# Generated by FakeRAM 2.0
VERSION 5.7 ;
BUSBITCHARS "[]" ;
PROPERTYDEFINITIONS
  MACRO width INTEGER ;
  MACRO depth INTEGER ;
  MACRO banks INTEGER ;
END PROPERTYDEFINITIONS
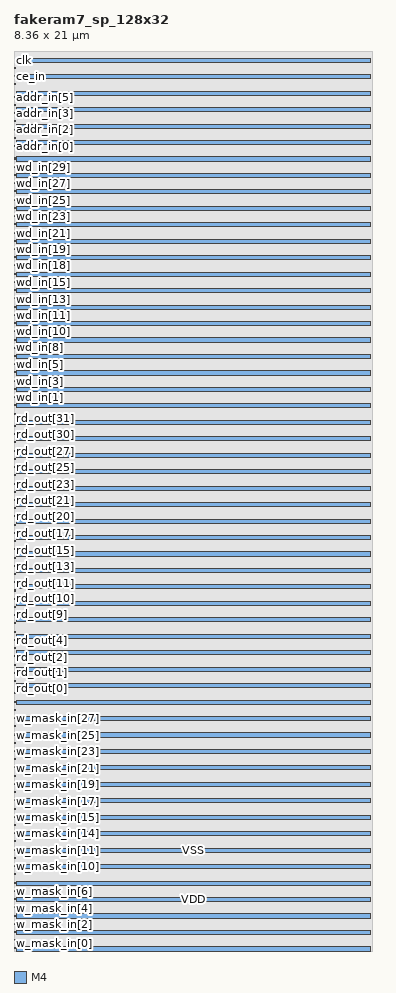
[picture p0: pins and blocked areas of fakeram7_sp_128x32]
MACRO fakeram7_sp_128x32
  PROPERTY width 32 ;
  PROPERTY depth 128 ;
  PROPERTY banks 2 ;
  FOREIGN fakeram7_sp_128x32 0 0 ;
  SYMMETRY X Y ;
  SIZE 8.360 BY 21.000 ;
  CLASS BLOCK ;
  PIN w_mask_in[0]
    DIRECTION INPUT ;
    USE SIGNAL ;
    SHAPE ABUTMENT ;
    PORT
      LAYER M4 ;
      RECT 0.000 0.048 0.024 0.072 ;
    END
  END w_mask_in[0]
  PIN w_mask_in[1]
    DIRECTION INPUT ;
    USE SIGNAL ;
    SHAPE ABUTMENT ;
    PORT
      LAYER M4 ;
      RECT 0.000 0.240 0.024 0.264 ;
    END
  END w_mask_in[1]
  PIN w_mask_in[2]
    DIRECTION INPUT ;
    USE SIGNAL ;
    SHAPE ABUTMENT ;
    PORT
      LAYER M4 ;
      RECT 0.000 0.432 0.024 0.456 ;
    END
  END w_mask_in[2]
  PIN w_mask_in[3]
    DIRECTION INPUT ;
    USE SIGNAL ;
    SHAPE ABUTMENT ;
    PORT
      LAYER M4 ;
      RECT 0.000 0.624 0.024 0.648 ;
    END
  END w_mask_in[3]
  PIN w_mask_in[4]
    DIRECTION INPUT ;
    USE SIGNAL ;
    SHAPE ABUTMENT ;
    PORT
      LAYER M4 ;
      RECT 0.000 0.816 0.024 0.840 ;
    END
  END w_mask_in[4]
  PIN w_mask_in[5]
    DIRECTION INPUT ;
    USE SIGNAL ;
    SHAPE ABUTMENT ;
    PORT
      LAYER M4 ;
      RECT 0.000 1.008 0.024 1.032 ;
    END
  END w_mask_in[5]
  PIN w_mask_in[6]
    DIRECTION INPUT ;
    USE SIGNAL ;
    SHAPE ABUTMENT ;
    PORT
      LAYER M4 ;
      RECT 0.000 1.200 0.024 1.224 ;
    END
  END w_mask_in[6]
  PIN w_mask_in[7]
    DIRECTION INPUT ;
    USE SIGNAL ;
    SHAPE ABUTMENT ;
    PORT
      LAYER M4 ;
      RECT 0.000 1.392 0.024 1.416 ;
    END
  END w_mask_in[7]
  PIN w_mask_in[8]
    DIRECTION INPUT ;
    USE SIGNAL ;
    SHAPE ABUTMENT ;
    PORT
      LAYER M4 ;
      RECT 0.000 1.584 0.024 1.608 ;
    END
  END w_mask_in[8]
  PIN w_mask_in[9]
    DIRECTION INPUT ;
    USE SIGNAL ;
    SHAPE ABUTMENT ;
    PORT
      LAYER M4 ;
      RECT 0.000 1.776 0.024 1.800 ;
    END
  END w_mask_in[9]
  PIN w_mask_in[10]
    DIRECTION INPUT ;
    USE SIGNAL ;
    SHAPE ABUTMENT ;
    PORT
      LAYER M4 ;
      RECT 0.000 1.968 0.024 1.992 ;
    END
  END w_mask_in[10]
  PIN w_mask_in[11]
    DIRECTION INPUT ;
    USE SIGNAL ;
    SHAPE ABUTMENT ;
    PORT
      LAYER M4 ;
      RECT 0.000 2.160 0.024 2.184 ;
    END
  END w_mask_in[11]
  PIN w_mask_in[12]
    DIRECTION INPUT ;
    USE SIGNAL ;
    SHAPE ABUTMENT ;
    PORT
      LAYER M4 ;
      RECT 0.000 2.352 0.024 2.376 ;
    END
  END w_mask_in[12]
  PIN w_mask_in[13]
    DIRECTION INPUT ;
    USE SIGNAL ;
    SHAPE ABUTMENT ;
    PORT
      LAYER M4 ;
      RECT 0.000 2.544 0.024 2.568 ;
    END
  END w_mask_in[13]
  PIN w_mask_in[14]
    DIRECTION INPUT ;
    USE SIGNAL ;
    SHAPE ABUTMENT ;
    PORT
      LAYER M4 ;
      RECT 0.000 2.736 0.024 2.760 ;
    END
  END w_mask_in[14]
  PIN w_mask_in[15]
    DIRECTION INPUT ;
    USE SIGNAL ;
    SHAPE ABUTMENT ;
    PORT
      LAYER M4 ;
      RECT 0.000 2.928 0.024 2.952 ;
    END
  END w_mask_in[15]
  PIN w_mask_in[16]
    DIRECTION INPUT ;
    USE SIGNAL ;
    SHAPE ABUTMENT ;
    PORT
      LAYER M4 ;
      RECT 0.000 3.120 0.024 3.144 ;
    END
  END w_mask_in[16]
  PIN w_mask_in[17]
    DIRECTION INPUT ;
    USE SIGNAL ;
    SHAPE ABUTMENT ;
    PORT
      LAYER M4 ;
      RECT 0.000 3.312 0.024 3.336 ;
    END
  END w_mask_in[17]
  PIN w_mask_in[18]
    DIRECTION INPUT ;
    USE SIGNAL ;
    SHAPE ABUTMENT ;
    PORT
      LAYER M4 ;
      RECT 0.000 3.504 0.024 3.528 ;
    END
  END w_mask_in[18]
  PIN w_mask_in[19]
    DIRECTION INPUT ;
    USE SIGNAL ;
    SHAPE ABUTMENT ;
    PORT
      LAYER M4 ;
      RECT 0.000 3.696 0.024 3.720 ;
    END
  END w_mask_in[19]
  PIN w_mask_in[20]
    DIRECTION INPUT ;
    USE SIGNAL ;
    SHAPE ABUTMENT ;
    PORT
      LAYER M4 ;
      RECT 0.000 3.888 0.024 3.912 ;
    END
  END w_mask_in[20]
  PIN w_mask_in[21]
    DIRECTION INPUT ;
    USE SIGNAL ;
    SHAPE ABUTMENT ;
    PORT
      LAYER M4 ;
      RECT 0.000 4.080 0.024 4.104 ;
    END
  END w_mask_in[21]
  PIN w_mask_in[22]
    DIRECTION INPUT ;
    USE SIGNAL ;
    SHAPE ABUTMENT ;
    PORT
      LAYER M4 ;
      RECT 0.000 4.272 0.024 4.296 ;
    END
  END w_mask_in[22]
  PIN w_mask_in[23]
    DIRECTION INPUT ;
    USE SIGNAL ;
    SHAPE ABUTMENT ;
    PORT
      LAYER M4 ;
      RECT 0.000 4.464 0.024 4.488 ;
    END
  END w_mask_in[23]
  PIN w_mask_in[24]
    DIRECTION INPUT ;
    USE SIGNAL ;
    SHAPE ABUTMENT ;
    PORT
      LAYER M4 ;
      RECT 0.000 4.656 0.024 4.680 ;
    END
  END w_mask_in[24]
  PIN w_mask_in[25]
    DIRECTION INPUT ;
    USE SIGNAL ;
    SHAPE ABUTMENT ;
    PORT
      LAYER M4 ;
      RECT 0.000 4.848 0.024 4.872 ;
    END
  END w_mask_in[25]
  PIN w_mask_in[26]
    DIRECTION INPUT ;
    USE SIGNAL ;
    SHAPE ABUTMENT ;
    PORT
      LAYER M4 ;
      RECT 0.000 5.040 0.024 5.064 ;
    END
  END w_mask_in[26]
  PIN w_mask_in[27]
    DIRECTION INPUT ;
    USE SIGNAL ;
    SHAPE ABUTMENT ;
    PORT
      LAYER M4 ;
      RECT 0.000 5.232 0.024 5.256 ;
    END
  END w_mask_in[27]
  PIN w_mask_in[28]
    DIRECTION INPUT ;
    USE SIGNAL ;
    SHAPE ABUTMENT ;
    PORT
      LAYER M4 ;
      RECT 0.000 5.424 0.024 5.448 ;
    END
  END w_mask_in[28]
  PIN w_mask_in[29]
    DIRECTION INPUT ;
    USE SIGNAL ;
    SHAPE ABUTMENT ;
    PORT
      LAYER M4 ;
      RECT 0.000 5.616 0.024 5.640 ;
    END
  END w_mask_in[29]
  PIN w_mask_in[30]
    DIRECTION INPUT ;
    USE SIGNAL ;
    SHAPE ABUTMENT ;
    PORT
      LAYER M4 ;
      RECT 0.000 5.808 0.024 5.832 ;
    END
  END w_mask_in[30]
  PIN w_mask_in[31]
    DIRECTION INPUT ;
    USE SIGNAL ;
    SHAPE ABUTMENT ;
    PORT
      LAYER M4 ;
      RECT 0.000 6.000 0.024 6.024 ;
    END
  END w_mask_in[31]
  PIN rd_out[0]
    DIRECTION OUTPUT ;
    USE SIGNAL ;
    SHAPE ABUTMENT ;
    PORT
      LAYER M4 ;
      RECT 0.000 6.288 0.024 6.312 ;
    END
  END rd_out[0]
  PIN rd_out[1]
    DIRECTION OUTPUT ;
    USE SIGNAL ;
    SHAPE ABUTMENT ;
    PORT
      LAYER M4 ;
      RECT 0.000 6.480 0.024 6.504 ;
    END
  END rd_out[1]
  PIN rd_out[2]
    DIRECTION OUTPUT ;
    USE SIGNAL ;
    SHAPE ABUTMENT ;
    PORT
      LAYER M4 ;
      RECT 0.000 6.672 0.024 6.696 ;
    END
  END rd_out[2]
  PIN rd_out[3]
    DIRECTION OUTPUT ;
    USE SIGNAL ;
    SHAPE ABUTMENT ;
    PORT
      LAYER M4 ;
      RECT 0.000 6.864 0.024 6.888 ;
    END
  END rd_out[3]
  PIN rd_out[4]
    DIRECTION OUTPUT ;
    USE SIGNAL ;
    SHAPE ABUTMENT ;
    PORT
      LAYER M4 ;
      RECT 0.000 7.056 0.024 7.080 ;
    END
  END rd_out[4]
  PIN rd_out[5]
    DIRECTION OUTPUT ;
    USE SIGNAL ;
    SHAPE ABUTMENT ;
    PORT
      LAYER M4 ;
      RECT 0.000 7.248 0.024 7.272 ;
    END
  END rd_out[5]
  PIN rd_out[6]
    DIRECTION OUTPUT ;
    USE SIGNAL ;
    SHAPE ABUTMENT ;
    PORT
      LAYER M4 ;
      RECT 0.000 7.440 0.024 7.464 ;
    END
  END rd_out[6]
  PIN rd_out[7]
    DIRECTION OUTPUT ;
    USE SIGNAL ;
    SHAPE ABUTMENT ;
    PORT
      LAYER M4 ;
      RECT 0.000 7.632 0.024 7.656 ;
    END
  END rd_out[7]
  PIN rd_out[8]
    DIRECTION OUTPUT ;
    USE SIGNAL ;
    SHAPE ABUTMENT ;
    PORT
      LAYER M4 ;
      RECT 0.000 7.824 0.024 7.848 ;
    END
  END rd_out[8]
  PIN rd_out[9]
    DIRECTION OUTPUT ;
    USE SIGNAL ;
    SHAPE ABUTMENT ;
    PORT
      LAYER M4 ;
      RECT 0.000 8.016 0.024 8.040 ;
    END
  END rd_out[9]
  PIN rd_out[10]
    DIRECTION OUTPUT ;
    USE SIGNAL ;
    SHAPE ABUTMENT ;
    PORT
      LAYER M4 ;
      RECT 0.000 8.208 0.024 8.232 ;
    END
  END rd_out[10]
  PIN rd_out[11]
    DIRECTION OUTPUT ;
    USE SIGNAL ;
    SHAPE ABUTMENT ;
    PORT
      LAYER M4 ;
      RECT 0.000 8.400 0.024 8.424 ;
    END
  END rd_out[11]
  PIN rd_out[12]
    DIRECTION OUTPUT ;
    USE SIGNAL ;
    SHAPE ABUTMENT ;
    PORT
      LAYER M4 ;
      RECT 0.000 8.592 0.024 8.616 ;
    END
  END rd_out[12]
  PIN rd_out[13]
    DIRECTION OUTPUT ;
    USE SIGNAL ;
    SHAPE ABUTMENT ;
    PORT
      LAYER M4 ;
      RECT 0.000 8.784 0.024 8.808 ;
    END
  END rd_out[13]
  PIN rd_out[14]
    DIRECTION OUTPUT ;
    USE SIGNAL ;
    SHAPE ABUTMENT ;
    PORT
      LAYER M4 ;
      RECT 0.000 8.976 0.024 9.000 ;
    END
  END rd_out[14]
  PIN rd_out[15]
    DIRECTION OUTPUT ;
    USE SIGNAL ;
    SHAPE ABUTMENT ;
    PORT
      LAYER M4 ;
      RECT 0.000 9.168 0.024 9.192 ;
    END
  END rd_out[15]
  PIN rd_out[16]
    DIRECTION OUTPUT ;
    USE SIGNAL ;
    SHAPE ABUTMENT ;
    PORT
      LAYER M4 ;
      RECT 0.000 9.360 0.024 9.384 ;
    END
  END rd_out[16]
  PIN rd_out[17]
    DIRECTION OUTPUT ;
    USE SIGNAL ;
    SHAPE ABUTMENT ;
    PORT
      LAYER M4 ;
      RECT 0.000 9.552 0.024 9.576 ;
    END
  END rd_out[17]
  PIN rd_out[18]
    DIRECTION OUTPUT ;
    USE SIGNAL ;
    SHAPE ABUTMENT ;
    PORT
      LAYER M4 ;
      RECT 0.000 9.744 0.024 9.768 ;
    END
  END rd_out[18]
  PIN rd_out[19]
    DIRECTION OUTPUT ;
    USE SIGNAL ;
    SHAPE ABUTMENT ;
    PORT
      LAYER M4 ;
      RECT 0.000 9.936 0.024 9.960 ;
    END
  END rd_out[19]
  PIN rd_out[20]
    DIRECTION OUTPUT ;
    USE SIGNAL ;
    SHAPE ABUTMENT ;
    PORT
      LAYER M4 ;
      RECT 0.000 10.128 0.024 10.152 ;
    END
  END rd_out[20]
  PIN rd_out[21]
    DIRECTION OUTPUT ;
    USE SIGNAL ;
    SHAPE ABUTMENT ;
    PORT
      LAYER M4 ;
      RECT 0.000 10.320 0.024 10.344 ;
    END
  END rd_out[21]
  PIN rd_out[22]
    DIRECTION OUTPUT ;
    USE SIGNAL ;
    SHAPE ABUTMENT ;
    PORT
      LAYER M4 ;
      RECT 0.000 10.512 0.024 10.536 ;
    END
  END rd_out[22]
  PIN rd_out[23]
    DIRECTION OUTPUT ;
    USE SIGNAL ;
    SHAPE ABUTMENT ;
    PORT
      LAYER M4 ;
      RECT 0.000 10.704 0.024 10.728 ;
    END
  END rd_out[23]
  PIN rd_out[24]
    DIRECTION OUTPUT ;
    USE SIGNAL ;
    SHAPE ABUTMENT ;
    PORT
      LAYER M4 ;
      RECT 0.000 10.896 0.024 10.920 ;
    END
  END rd_out[24]
  PIN rd_out[25]
    DIRECTION OUTPUT ;
    USE SIGNAL ;
    SHAPE ABUTMENT ;
    PORT
      LAYER M4 ;
      RECT 0.000 11.088 0.024 11.112 ;
    END
  END rd_out[25]
  PIN rd_out[26]
    DIRECTION OUTPUT ;
    USE SIGNAL ;
    SHAPE ABUTMENT ;
    PORT
      LAYER M4 ;
      RECT 0.000 11.280 0.024 11.304 ;
    END
  END rd_out[26]
  PIN rd_out[27]
    DIRECTION OUTPUT ;
    USE SIGNAL ;
    SHAPE ABUTMENT ;
    PORT
      LAYER M4 ;
      RECT 0.000 11.472 0.024 11.496 ;
    END
  END rd_out[27]
  PIN rd_out[28]
    DIRECTION OUTPUT ;
    USE SIGNAL ;
    SHAPE ABUTMENT ;
    PORT
      LAYER M4 ;
      RECT 0.000 11.664 0.024 11.688 ;
    END
  END rd_out[28]
  PIN rd_out[29]
    DIRECTION OUTPUT ;
    USE SIGNAL ;
    SHAPE ABUTMENT ;
    PORT
      LAYER M4 ;
      RECT 0.000 11.856 0.024 11.880 ;
    END
  END rd_out[29]
  PIN rd_out[30]
    DIRECTION OUTPUT ;
    USE SIGNAL ;
    SHAPE ABUTMENT ;
    PORT
      LAYER M4 ;
      RECT 0.000 12.048 0.024 12.072 ;
    END
  END rd_out[30]
  PIN rd_out[31]
    DIRECTION OUTPUT ;
    USE SIGNAL ;
    SHAPE ABUTMENT ;
    PORT
      LAYER M4 ;
      RECT 0.000 12.240 0.024 12.264 ;
    END
  END rd_out[31]
  PIN wd_in[0]
    DIRECTION INPUT ;
    USE SIGNAL ;
    SHAPE ABUTMENT ;
    PORT
      LAYER M4 ;
      RECT 0.000 12.528 0.024 12.552 ;
    END
  END wd_in[0]
  PIN wd_in[1]
    DIRECTION INPUT ;
    USE SIGNAL ;
    SHAPE ABUTMENT ;
    PORT
      LAYER M4 ;
      RECT 0.000 12.720 0.024 12.744 ;
    END
  END wd_in[1]
  PIN wd_in[2]
    DIRECTION INPUT ;
    USE SIGNAL ;
    SHAPE ABUTMENT ;
    PORT
      LAYER M4 ;
      RECT 0.000 12.912 0.024 12.936 ;
    END
  END wd_in[2]
  PIN wd_in[3]
    DIRECTION INPUT ;
    USE SIGNAL ;
    SHAPE ABUTMENT ;
    PORT
      LAYER M4 ;
      RECT 0.000 13.104 0.024 13.128 ;
    END
  END wd_in[3]
  PIN wd_in[4]
    DIRECTION INPUT ;
    USE SIGNAL ;
    SHAPE ABUTMENT ;
    PORT
      LAYER M4 ;
      RECT 0.000 13.296 0.024 13.320 ;
    END
  END wd_in[4]
  PIN wd_in[5]
    DIRECTION INPUT ;
    USE SIGNAL ;
    SHAPE ABUTMENT ;
    PORT
      LAYER M4 ;
      RECT 0.000 13.488 0.024 13.512 ;
    END
  END wd_in[5]
  PIN wd_in[6]
    DIRECTION INPUT ;
    USE SIGNAL ;
    SHAPE ABUTMENT ;
    PORT
      LAYER M4 ;
      RECT 0.000 13.680 0.024 13.704 ;
    END
  END wd_in[6]
  PIN wd_in[7]
    DIRECTION INPUT ;
    USE SIGNAL ;
    SHAPE ABUTMENT ;
    PORT
      LAYER M4 ;
      RECT 0.000 13.872 0.024 13.896 ;
    END
  END wd_in[7]
  PIN wd_in[8]
    DIRECTION INPUT ;
    USE SIGNAL ;
    SHAPE ABUTMENT ;
    PORT
      LAYER M4 ;
      RECT 0.000 14.064 0.024 14.088 ;
    END
  END wd_in[8]
  PIN wd_in[9]
    DIRECTION INPUT ;
    USE SIGNAL ;
    SHAPE ABUTMENT ;
    PORT
      LAYER M4 ;
      RECT 0.000 14.256 0.024 14.280 ;
    END
  END wd_in[9]
  PIN wd_in[10]
    DIRECTION INPUT ;
    USE SIGNAL ;
    SHAPE ABUTMENT ;
    PORT
      LAYER M4 ;
      RECT 0.000 14.448 0.024 14.472 ;
    END
  END wd_in[10]
  PIN wd_in[11]
    DIRECTION INPUT ;
    USE SIGNAL ;
    SHAPE ABUTMENT ;
    PORT
      LAYER M4 ;
      RECT 0.000 14.640 0.024 14.664 ;
    END
  END wd_in[11]
  PIN wd_in[12]
    DIRECTION INPUT ;
    USE SIGNAL ;
    SHAPE ABUTMENT ;
    PORT
      LAYER M4 ;
      RECT 0.000 14.832 0.024 14.856 ;
    END
  END wd_in[12]
  PIN wd_in[13]
    DIRECTION INPUT ;
    USE SIGNAL ;
    SHAPE ABUTMENT ;
    PORT
      LAYER M4 ;
      RECT 0.000 15.024 0.024 15.048 ;
    END
  END wd_in[13]
  PIN wd_in[14]
    DIRECTION INPUT ;
    USE SIGNAL ;
    SHAPE ABUTMENT ;
    PORT
      LAYER M4 ;
      RECT 0.000 15.216 0.024 15.240 ;
    END
  END wd_in[14]
  PIN wd_in[15]
    DIRECTION INPUT ;
    USE SIGNAL ;
    SHAPE ABUTMENT ;
    PORT
      LAYER M4 ;
      RECT 0.000 15.408 0.024 15.432 ;
    END
  END wd_in[15]
  PIN wd_in[16]
    DIRECTION INPUT ;
    USE SIGNAL ;
    SHAPE ABUTMENT ;
    PORT
      LAYER M4 ;
      RECT 0.000 15.600 0.024 15.624 ;
    END
  END wd_in[16]
  PIN wd_in[17]
    DIRECTION INPUT ;
    USE SIGNAL ;
    SHAPE ABUTMENT ;
    PORT
      LAYER M4 ;
      RECT 0.000 15.792 0.024 15.816 ;
    END
  END wd_in[17]
  PIN wd_in[18]
    DIRECTION INPUT ;
    USE SIGNAL ;
    SHAPE ABUTMENT ;
    PORT
      LAYER M4 ;
      RECT 0.000 15.984 0.024 16.008 ;
    END
  END wd_in[18]
  PIN wd_in[19]
    DIRECTION INPUT ;
    USE SIGNAL ;
    SHAPE ABUTMENT ;
    PORT
      LAYER M4 ;
      RECT 0.000 16.176 0.024 16.200 ;
    END
  END wd_in[19]
  PIN wd_in[20]
    DIRECTION INPUT ;
    USE SIGNAL ;
    SHAPE ABUTMENT ;
    PORT
      LAYER M4 ;
      RECT 0.000 16.368 0.024 16.392 ;
    END
  END wd_in[20]
  PIN wd_in[21]
    DIRECTION INPUT ;
    USE SIGNAL ;
    SHAPE ABUTMENT ;
    PORT
      LAYER M4 ;
      RECT 0.000 16.560 0.024 16.584 ;
    END
  END wd_in[21]
  PIN wd_in[22]
    DIRECTION INPUT ;
    USE SIGNAL ;
    SHAPE ABUTMENT ;
    PORT
      LAYER M4 ;
      RECT 0.000 16.752 0.024 16.776 ;
    END
  END wd_in[22]
  PIN wd_in[23]
    DIRECTION INPUT ;
    USE SIGNAL ;
    SHAPE ABUTMENT ;
    PORT
      LAYER M4 ;
      RECT 0.000 16.944 0.024 16.968 ;
    END
  END wd_in[23]
  PIN wd_in[24]
    DIRECTION INPUT ;
    USE SIGNAL ;
    SHAPE ABUTMENT ;
    PORT
      LAYER M4 ;
      RECT 0.000 17.136 0.024 17.160 ;
    END
  END wd_in[24]
  PIN wd_in[25]
    DIRECTION INPUT ;
    USE SIGNAL ;
    SHAPE ABUTMENT ;
    PORT
      LAYER M4 ;
      RECT 0.000 17.328 0.024 17.352 ;
    END
  END wd_in[25]
  PIN wd_in[26]
    DIRECTION INPUT ;
    USE SIGNAL ;
    SHAPE ABUTMENT ;
    PORT
      LAYER M4 ;
      RECT 0.000 17.520 0.024 17.544 ;
    END
  END wd_in[26]
  PIN wd_in[27]
    DIRECTION INPUT ;
    USE SIGNAL ;
    SHAPE ABUTMENT ;
    PORT
      LAYER M4 ;
      RECT 0.000 17.712 0.024 17.736 ;
    END
  END wd_in[27]
  PIN wd_in[28]
    DIRECTION INPUT ;
    USE SIGNAL ;
    SHAPE ABUTMENT ;
    PORT
      LAYER M4 ;
      RECT 0.000 17.904 0.024 17.928 ;
    END
  END wd_in[28]
  PIN wd_in[29]
    DIRECTION INPUT ;
    USE SIGNAL ;
    SHAPE ABUTMENT ;
    PORT
      LAYER M4 ;
      RECT 0.000 18.096 0.024 18.120 ;
    END
  END wd_in[29]
  PIN wd_in[30]
    DIRECTION INPUT ;
    USE SIGNAL ;
    SHAPE ABUTMENT ;
    PORT
      LAYER M4 ;
      RECT 0.000 18.288 0.024 18.312 ;
    END
  END wd_in[30]
  PIN wd_in[31]
    DIRECTION INPUT ;
    USE SIGNAL ;
    SHAPE ABUTMENT ;
    PORT
      LAYER M4 ;
      RECT 0.000 18.480 0.024 18.504 ;
    END
  END wd_in[31]
  PIN addr_in[0]
    DIRECTION INPUT ;
    USE SIGNAL ;
    SHAPE ABUTMENT ;
    PORT
      LAYER M4 ;
      RECT 0.000 18.768 0.024 18.792 ;
    END
  END addr_in[0]
  PIN addr_in[1]
    DIRECTION INPUT ;
    USE SIGNAL ;
    SHAPE ABUTMENT ;
    PORT
      LAYER M4 ;
      RECT 0.000 18.960 0.024 18.984 ;
    END
  END addr_in[1]
  PIN addr_in[2]
    DIRECTION INPUT ;
    USE SIGNAL ;
    SHAPE ABUTMENT ;
    PORT
      LAYER M4 ;
      RECT 0.000 19.152 0.024 19.176 ;
    END
  END addr_in[2]
  PIN addr_in[3]
    DIRECTION INPUT ;
    USE SIGNAL ;
    SHAPE ABUTMENT ;
    PORT
      LAYER M4 ;
      RECT 0.000 19.344 0.024 19.368 ;
    END
  END addr_in[3]
  PIN addr_in[4]
    DIRECTION INPUT ;
    USE SIGNAL ;
    SHAPE ABUTMENT ;
    PORT
      LAYER M4 ;
      RECT 0.000 19.536 0.024 19.560 ;
    END
  END addr_in[4]
  PIN addr_in[5]
    DIRECTION INPUT ;
    USE SIGNAL ;
    SHAPE ABUTMENT ;
    PORT
      LAYER M4 ;
      RECT 0.000 19.728 0.024 19.752 ;
    END
  END addr_in[5]
  PIN addr_in[6]
    DIRECTION INPUT ;
    USE SIGNAL ;
    SHAPE ABUTMENT ;
    PORT
      LAYER M4 ;
      RECT 0.000 19.920 0.024 19.944 ;
    END
  END addr_in[6]
  PIN we_in
    DIRECTION INPUT ;
    USE SIGNAL ;
    SHAPE ABUTMENT ;
    PORT
      LAYER M4 ;
      RECT 0.000 20.208 0.024 20.232 ;
    END
  END we_in
  PIN ce_in
    DIRECTION INPUT ;
    USE SIGNAL ;
    SHAPE ABUTMENT ;
    PORT
      LAYER M4 ;
      RECT 0.000 20.400 0.024 20.424 ;
    END
  END ce_in
  PIN clk
    DIRECTION INPUT ;
    USE SIGNAL ;
    SHAPE ABUTMENT ;
    PORT
      LAYER M4 ;
      RECT 0.000 20.592 0.024 20.616 ;
    END
  END clk
  PIN VSS
    DIRECTION INOUT ;
    USE GROUND ;
    PORT
      LAYER M4 ;
      RECT 0.048 0.000 8.312 0.096 ;
      RECT 0.048 0.768 8.312 0.864 ;
      RECT 0.048 1.536 8.312 1.632 ;
      RECT 0.048 2.304 8.312 2.400 ;
      RECT 0.048 3.072 8.312 3.168 ;
      RECT 0.048 3.840 8.312 3.936 ;
      RECT 0.048 4.608 8.312 4.704 ;
      RECT 0.048 5.376 8.312 5.472 ;
      RECT 0.048 6.144 8.312 6.240 ;
      RECT 0.048 6.912 8.312 7.008 ;
      RECT 0.048 7.680 8.312 7.776 ;
      RECT 0.048 8.448 8.312 8.544 ;
      RECT 0.048 9.216 8.312 9.312 ;
      RECT 0.048 9.984 8.312 10.080 ;
      RECT 0.048 10.752 8.312 10.848 ;
      RECT 0.048 11.520 8.312 11.616 ;
      RECT 0.048 12.288 8.312 12.384 ;
      RECT 0.048 13.056 8.312 13.152 ;
      RECT 0.048 13.824 8.312 13.920 ;
      RECT 0.048 14.592 8.312 14.688 ;
      RECT 0.048 15.360 8.312 15.456 ;
      RECT 0.048 16.128 8.312 16.224 ;
      RECT 0.048 16.896 8.312 16.992 ;
      RECT 0.048 17.664 8.312 17.760 ;
      RECT 0.048 18.432 8.312 18.528 ;
      RECT 0.048 19.200 8.312 19.296 ;
      RECT 0.048 19.968 8.312 20.064 ;
      RECT 0.048 20.736 8.312 20.832 ;
    END
  END VSS
  PIN VDD
    DIRECTION INOUT ;
    USE POWER ;
    PORT
      LAYER M4 ;
      RECT 0.048 0.384 8.312 0.480 ;
      RECT 0.048 1.152 8.312 1.248 ;
      RECT 0.048 1.920 8.312 2.016 ;
      RECT 0.048 2.688 8.312 2.784 ;
      RECT 0.048 3.456 8.312 3.552 ;
      RECT 0.048 4.224 8.312 4.320 ;
      RECT 0.048 4.992 8.312 5.088 ;
      RECT 0.048 5.760 8.312 5.856 ;
      RECT 0.048 6.528 8.312 6.624 ;
      RECT 0.048 7.296 8.312 7.392 ;
      RECT 0.048 8.064 8.312 8.160 ;
      RECT 0.048 8.832 8.312 8.928 ;
      RECT 0.048 9.600 8.312 9.696 ;
      RECT 0.048 10.368 8.312 10.464 ;
      RECT 0.048 11.136 8.312 11.232 ;
      RECT 0.048 11.904 8.312 12.000 ;
      RECT 0.048 12.672 8.312 12.768 ;
      RECT 0.048 13.440 8.312 13.536 ;
      RECT 0.048 14.208 8.312 14.304 ;
      RECT 0.048 14.976 8.312 15.072 ;
      RECT 0.048 15.744 8.312 15.840 ;
      RECT 0.048 16.512 8.312 16.608 ;
      RECT 0.048 17.280 8.312 17.376 ;
      RECT 0.048 18.048 8.312 18.144 ;
      RECT 0.048 18.816 8.312 18.912 ;
      RECT 0.048 19.584 8.312 19.680 ;
      RECT 0.048 20.352 8.312 20.448 ;
    END
  END VDD
  OBS
    LAYER M1 ;
    RECT 0 0 8.360 21.000 ;
    LAYER M2 ;
    RECT 0 0 8.360 21.000 ;
    LAYER M3 ;
    RECT 0 0 8.360 21.000 ;
    LAYER M4 ;
    RECT 0 0 8.360 21.000 ;
  END
END fakeram7_sp_128x32

END LIBRARY
